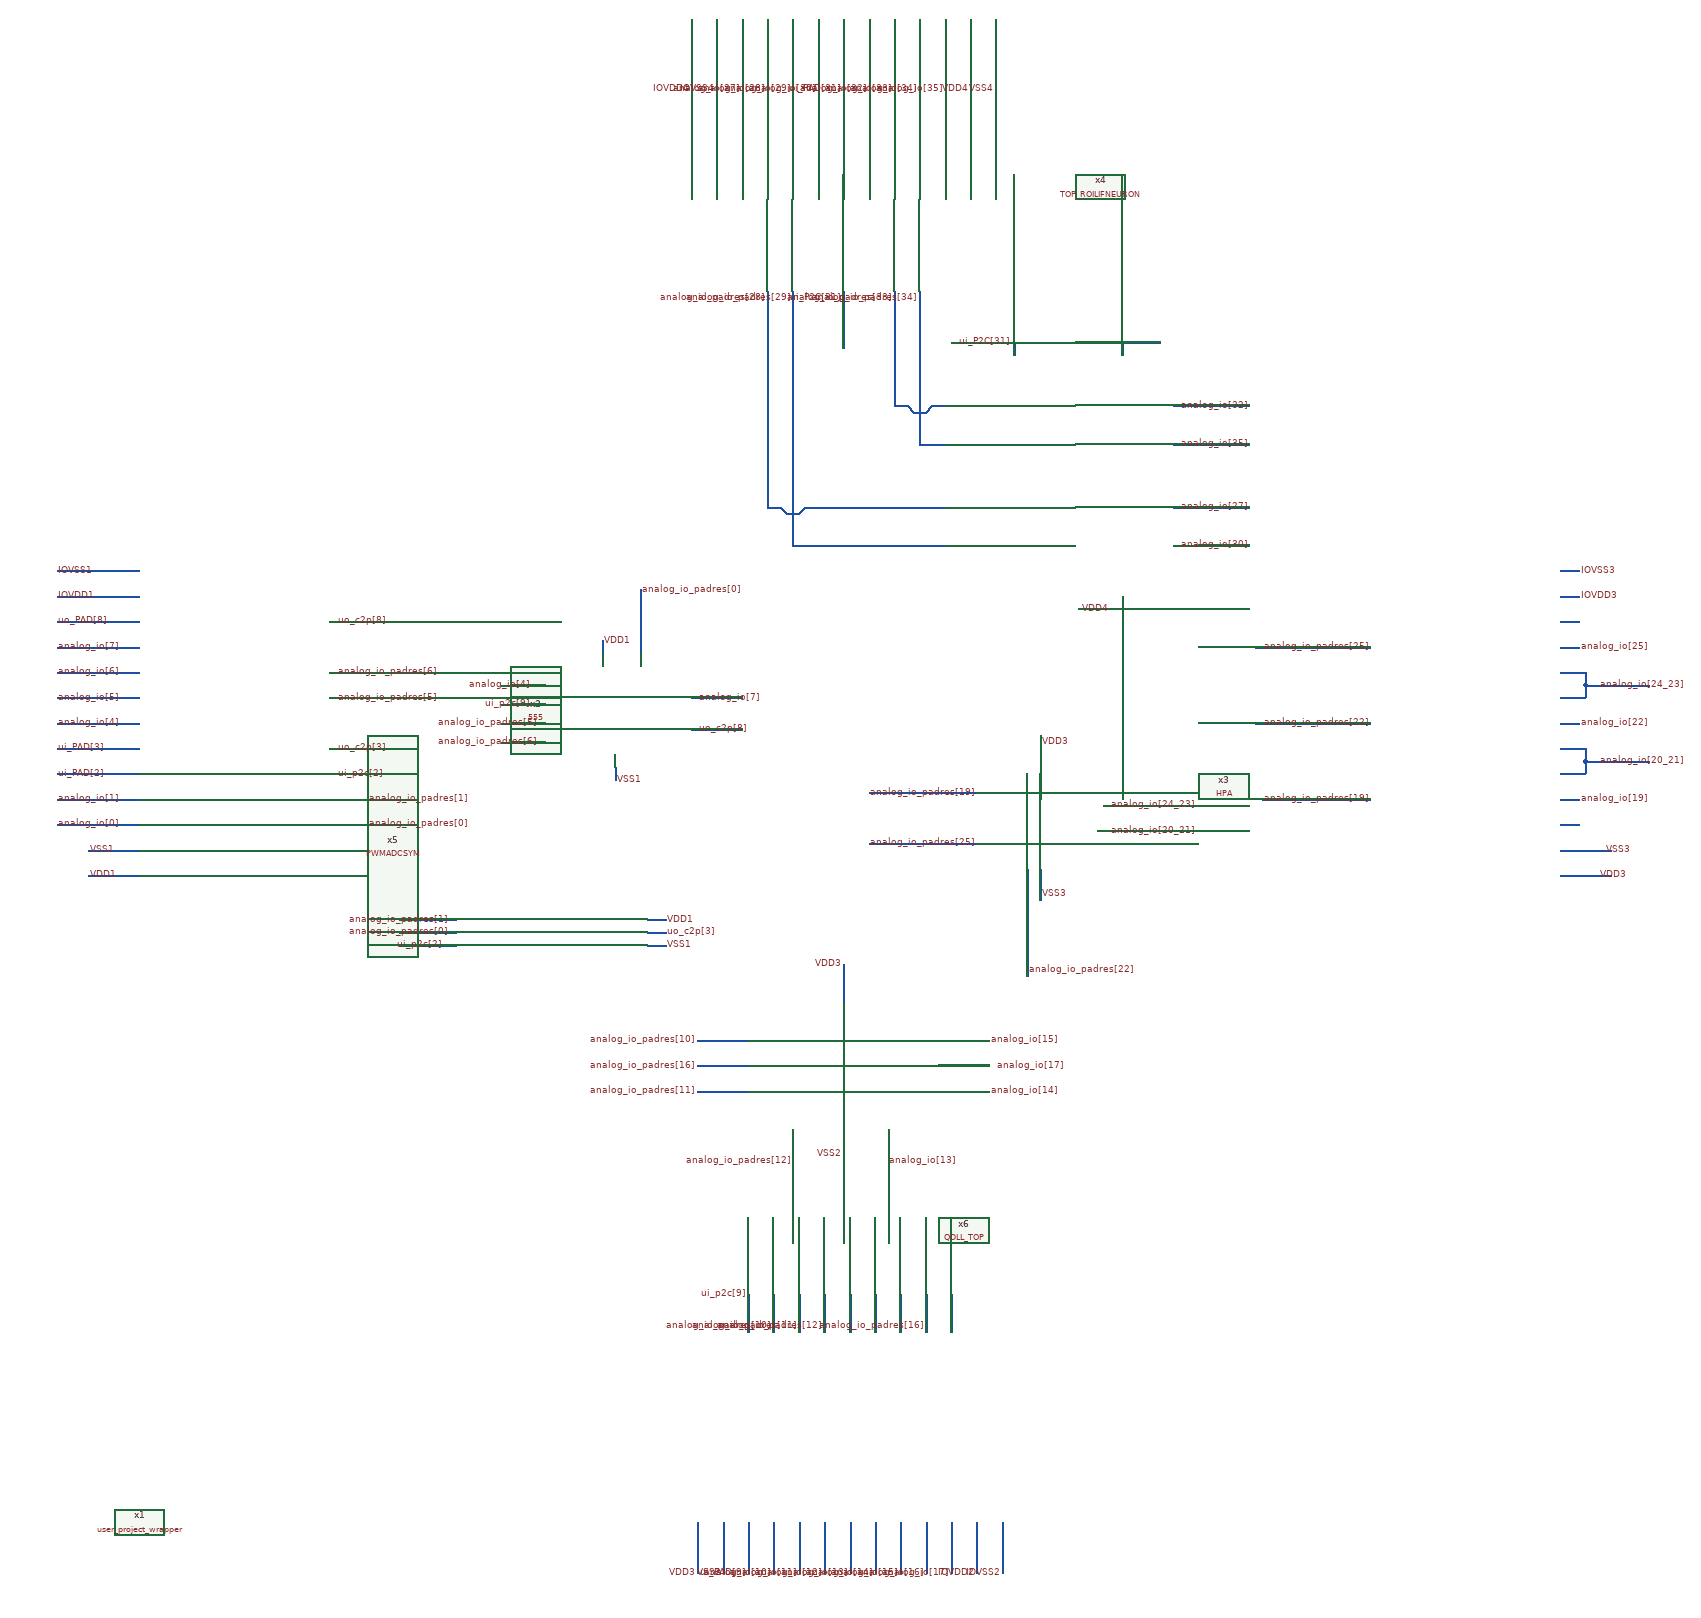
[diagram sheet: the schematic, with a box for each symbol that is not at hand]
v {xschem version=3.4.6 file_version=1.2}
G {}
K {}
V {}
S {}
E {}
N 1550 -1860 1610 -1860 {lab=#net1}
N 1030 -2370 1030 -2240 {lab=analog_io[29]}
N 990 -2370 990 -2240 {lab=analog_io[28]}
N 1230 -2370 1230 -2240 {lab=analog_io[34]}
N 1190 -2370 1190 -2240 {lab=analog_io[33]}
N 1070 -2370 1070 -2240 {lab=analog_io[30]}
N 950 -2370 950 -2240 {lab=analog_io[27]}
N 1110 -2370 1110 -2240 {lab=ui_PAD[31]}
N 1150 -2370 1150 -2240 {lab=analog_io[32]}
N 1270 -2370 1270 -2240 {lab=analog_io[35]}
N 910 -2370 910 -2240 {lab=IOVSS4}
N 870 -2370 870 -2240 {lab=IOVDD4}
N 1350 -2370 1350 -2240 {lab=VSS4}
N 1310 -2370 1310 -2240 {lab=VDD4}
N 1630 -1700 1750 -1700 {lab=analog_io[35]}
N 1630 -1760 1750 -1760 {lab=analog_io[32]}
N 1630 -1600 1750 -1600 {lab=analog_io[27]}
N 1190 -1940 1190 -1760 {lab=analog_io_padres[33]}
N 1630 -1540 1750 -1540 {lab=analog_io[30]}
N 1190 -1760 1210 -1760 {lab=analog_io_padres[33]}
N 1210 -1760 1220 -1750 {lab=analog_io_padres[33]}
N 1220 -1750 1240 -1750 {lab=analog_io_padres[33]}
N 1240 -1750 1250 -1760 {lab=analog_io_padres[33]}
N 990 -1600 1010 -1600 {lab=analog_io_padres[28]}
N 990 -1940 990 -1600 {lab=analog_io_padres[28]}
N 1010 -1600 1020 -1590 {lab=analog_io_padres[28]}
N 1020 -1590 1040 -1590 {lab=analog_io_padres[28]}
N 1040 -1590 1050 -1600 {lab=analog_io_padres[28]}
N 1380 -1860 1380 -1840 {lab=ui_P2C[31]}
N 1280 -1860 1380 -1860 {lab=ui_P2C[31]}
N 1550 -1860 1550 -1840 {lab=#net1}
N 1550 -1460 1550 -1440 {lab=VDD4}
N 1480 -1440 1550 -1440 {lab=VDD4}
N 1250 -1760 1270 -1760 {lab=analog_io_padres[33]}
N 1230 -1700 1270 -1700 {lab=analog_io_padres[34]}
N 1050 -1600 1270 -1600 {lab=analog_io_padres[28]}
N 1030 -1540 1270 -1540 {lab=analog_io_padres[29]}
N 1230 -1940 1230 -1700 {lab=analog_io_padres[34]}
N 1030 -1940 1030 -1540 {lab=analog_io_padres[29]}
N 1110 -1940 1110 -1850 {lab=ui_P2C[31]}
N -130 -1380 0 -1380 {lab=analog_io[7]}
N -130 -1260 0 -1260 {lab=analog_io[4]}
N 570 -1320 640 -1320 {lab=analog_io[4]}
N 870 -1300 950 -1300 {lab=analog_io[7]}
N -80 -1060 0 -1060 {lab=VSS1}
N -80 -1020 0 -1020 {lab=VDD1}
N 800 -950 830 -950 {lab=VDD1}
N 730 -1390 730 -1370 {lab=VDD1}
N 800 -910 830 -910 {lab=VSS1}
N 750 -1190 750 -1170 {lab=VSS1}
N 790 -1470 790 -1370 {lab=analog_io_padres[0]}
N 300 -1100 360 -1100 {lab=analog_io_padres[0]}
N 300 -1140 360 -1140 {lab=analog_io_padres[1]}
N 410 -930 500 -930 {lab=analog_io_padres[0]}
N 410 -950 500 -950 {lab=analog_io_padres[1]}
N 410 -910 500 -910 {lab=ui_p2c[2]}
N 800 -930 830 -930 {lab=uo_c2p[3]}
N 300 -1180 340 -1180 {lab=ui_p2c[2]}
N 300 -1220 340 -1220 {lab=uo_c2p[3]}
N 300 -1340 350 -1340 {lab=analog_io_padres[6]}
N 300 -1300 350 -1300 {lab=analog_io_padres[5]}
N 570 -1290 640 -1290 {lab=ui_p2c[9]}
N 570 -1260 640 -1260 {lab=analog_io_padres[5]}
N 570 -1230 640 -1230 {lab=analog_io_padres[6]}
N 300 -1420 340 -1420 {lab=uo_c2p[8]}
N 870 -1250 950 -1250 {lab=uo_c2p[8]}
N 960 -360 960 -300 {lab=ui_p2c[9]}
N -130 -1100 0 -1100 {lab=analog_io[0]}
N -130 -1140 0 -1140 {lab=analog_io[1]}
N -130 -1180 0 -1180 {lab=ui_PAD[2]}
N -130 -1220 0 -1220 {lab=ui_PAD[3]}
N -130 -1300 0 -1300 {lab=analog_io[5]}
N -130 -1340 0 -1340 {lab=analog_io[6]}
N -130 -1420 0 -1420 {lab=uo_PAD[8]}
N -130 -1500 0 -1500 {lab=IOVSS1}
N -130 -1460 0 -1460 {lab=IOVDD1}
N 1420 -1240 1420 -1190 {lab=VDD3}
N 1420 -1030 1420 -980 {lab=VSS3}
N 2240 -1020 2320 -1020 {lab=VDD3}
N 2240 -1060 2320 -1060 {lab=VSS3}
N 1520 -1130 1620 -1130 {lab=analog_io[24_23]}
N 1510 -1090 1610 -1090 {lab=analog_io[20_21]}
N 2240 -1180 2280 -1180 {lab=analog_io[20_21]}
N 2280 -1200 2280 -1180 {lab=analog_io[20_21]}
N 2240 -1220 2280 -1220 {lab=analog_io[20_21]}
N 2280 -1200 2380 -1200 {lab=analog_io[20_21]}
N 2280 -1220 2280 -1200 {lab=analog_io[20_21]}
N 2240 -1300 2280 -1300 {lab=analog_io[24_23]}
N 2280 -1320 2280 -1300 {lab=analog_io[24_23]}
N 2240 -1340 2280 -1340 {lab=analog_io[24_23]}
N 2280 -1320 2380 -1320 {lab=analog_io[24_23]}
N 2280 -1340 2280 -1320 {lab=analog_io[24_23]}
N 1400 -1030 1400 -860 {lab=analog_io_padres[22]}
N 1760 -1260 1940 -1260 {lab=analog_io_padres[22]}
N 1760 -1380 1940 -1380 {lab=analog_io_padres[25]}
N 1770 -1140 1940 -1140 {lab=analog_io_padres[19]}
N 1150 -1070 1320 -1070 {lab=analog_io_padres[25]}
N 1150 -1150 1320 -1150 {lab=analog_io_padres[19]}
N 2240 -1500 2270 -1500 {lab=IOVSS3}
N 2240 -1460 2270 -1460 {lab=IOVDD3}
N 2240 -1420 2270 -1420 {lab=#net2}
N 2240 -1100 2270 -1100 {lab=#net3}
N 1260 -760 1340 -760 {lab=analog_io[15]}
N 1260 -720 1340 -720 {lab=#net4}
N 1260 -680 1340 -680 {lab=analog_io_padres[14]}
N 880 -760 960 -760 {lab=analog_io_padres[10]}
N 880 -720 960 -720 {lab=analog_io_padres[16]}
N 880 -680 960 -680 {lab=analog_io_padres[11]}
N 1030 -620 1030 -570 {lab=analog_io_padres[12]}
N 1180 -620 1180 -570 {lab=analog_io[13]}
N 2240 -1380 2270 -1380 {lab=analog_io[25]}
N 2240 -1260 2270 -1260 {lab=analog_io[22]}
N 2240 -1140 2270 -1140 {lab=analog_io[19]}
N 880 0 880 80 {lab=VDD3}
N 920 0 920 80 {lab=VSS2}
N 960 0 960 80 {lab=ui_PAD[9]}
N 1000 0 1000 80 {lab=analog_io[10]}
N 1040 0 1040 80 {lab=analog_io[11]}
N 1080 0 1080 80 {lab=analog_io[12]}
N 1120 0 1120 80 {lab=analog_io[13]}
N 1160 0 1160 80 {lab=analog_io[14]}
N 1200 0 1200 80 {lab=analog_io[15]}
N 1240 0 1240 80 {lab=analog_io[16]}
N 1280 0 1280 80 {lab=analog_io[17]}
N 1320 0 1320 80 {lab=IOVDD2}
N 1360 0 1360 80 {lab=IOVSS2}
N 1110 -880 1110 -820 {lab=VDD3}
N 1040 -360 1040 -300 {lab=analog_io_padres[11]}
N 1080 -360 1080 -300 {lab=analog_io_padres[12]}
N 1120 -360 1120 -300 {lab=#net5}
N 1240 -360 1240 -300 {lab=analog_io_padres[16]}
N 1280 -360 1280 -300 {lab=#net6}
N 1000 -360 1000 -300 {lab=analog_io_padres[10]}
N 1110 -620 1110 -570 {lab=VSS2}
N 1200 -360 1200 -300 {lab=#net7}
N 1160 -360 1160 -300 {lab=#net8}
C {user_project_wrapper.sym} 0 0 0 0 {name=x1}
C {IHP__MPC0349/dependencies/IHP__OSC3593/OSC3593-main/schematic/xschem/555.sym} 790 -1300 0 0 {name=x2}
C {IHP__MPC0349/dependencies/IHP__OPA2251/OPA2251-main/schematic/xschem/HPA.sym} 1400 -1110 0 0 {name=x3}
C {IHP__MPC0349/dependencies/IHP__OSC9996/OSC9996-main/schematic/xschem/TOP_ROILIFNEURON.sym} 1250 -1860 2 1 {name=x4}
C {IHP__MPC0349/dependencies/IHP__QDLL6501/QDLL6501-main/schematic/xschem/QDLL_TOP.sym} 1110 -720 0 0 {name=x6}
C {IHP__MPC0349/dependencies/IHP__OSC3593/OSC3593-main/schematic/xschem/PWMADCSYM.sym} 650 -930 0 0 {name=x5}
C {lab_wire.sym} 1640 -1540 2 0 {name=p4 sig_type=std_logic lab=analog_io[30]	}
C {lab_wire.sym} 1640 -1600 2 0 {name=p5 sig_type=std_logic lab=analog_io[27]	}
C {lab_wire.sym} 1640 -1700 2 0 {name=p6 sig_type=std_logic lab=analog_io[35]	}
C {lab_wire.sym} 1640 -1760 2 0 {name=p7 sig_type=std_logic lab=analog_io[32]	}
C {lab_wire.sym} 1530 -1440 0 0 {name=p8 sig_type=std_logic lab=VDD4	}
C {lab_wire.sym} 1420 -990 0 1 {name=p10 sig_type=std_logic lab=VSS3}
C {lab_wire.sym} 1290 -1860 0 1 {name=p11 sig_type=std_logic lab=ui_P2C[31]	}
C {lab_wire.sym} 1030 -2260 1 0 {name=p12 sig_type=std_logic lab=analog_io[29]	}
C {lab_wire.sym} 990 -2260 1 0 {name=p13 sig_type=std_logic lab=analog_io[28]	}
C {lab_wire.sym} 1230 -2260 1 0 {name=p14 sig_type=std_logic lab=analog_io[34]	}
C {lab_wire.sym} 1190 -2260 1 0 {name=p15 sig_type=std_logic lab=analog_io[33]	}
C {lab_wire.sym} 1070 -2260 1 0 {name=p16 sig_type=std_logic lab=analog_io[30]	}
C {lab_wire.sym} 950 -2260 1 0 {name=p17 sig_type=std_logic lab=analog_io[27]	}
C {lab_wire.sym} 1110 -2260 1 0 {name=p18 sig_type=std_logic lab=ui_PAD[31]	}
C {lab_wire.sym} 1150 -2260 1 0 {name=p19 sig_type=std_logic lab=analog_io[32]	}
C {lab_wire.sym} 1270 -2260 1 0 {name=p20 sig_type=std_logic lab=analog_io[35]	}
C {lab_wire.sym} 910 -2260 1 0 {name=p21 sig_type=std_logic lab=IOVSS4	}
C {lab_wire.sym} 870 -2260 1 0 {name=p22 sig_type=std_logic lab=IOVDD4	}
C {lab_wire.sym} 1350 -2260 1 0 {name=p23 sig_type=std_logic lab=VSS4}
C {lab_wire.sym} 1310 -2260 1 0 {name=p24 sig_type=std_logic lab=VDD4	}
C {lab_wire.sym} 990 -1930 3 0 {name=p26 sig_type=std_logic lab=analog_io_padres[28]	}
C {lab_wire.sym} 1030 -1930 3 0 {name=p1 sig_type=std_logic lab=analog_io_padres[29]	}
C {lab_wire.sym} 1230 -1930 1 1 {name=p29 sig_type=std_logic lab=analog_io_padres[34]	}
C {lab_wire.sym} 1190 -1930 1 1 {name=p27 sig_type=std_logic lab=analog_io_padres[33]	}
C {lab_wire.sym} 1110 -1930 3 0 {name=p2 sig_type=std_logic lab=ui_P2C[31]	}
C {lab_wire.sym} 880 -1300 0 1 {name=p3 sig_type=std_logic lab=analog_io[7]	}
C {lab_wire.sym} -130 -1380 2 0 {name=p9 sig_type=std_logic lab=analog_io[7]	}
C {lab_wire.sym} -130 -1260 2 0 {name=p25 sig_type=std_logic lab=analog_io[4]	}
C {lab_wire.sym} 620 -1320 0 0 {name=p28 sig_type=std_logic lab=analog_io[4]	}
C {lab_wire.sym} -80 -1020 2 0 {name=p30 sig_type=std_logic lab=VDD1}
C {lab_wire.sym} -80 -1060 2 0 {name=p31 sig_type=std_logic lab=VSS1}
C {lab_wire.sym} 830 -950 0 1 {name=p32 sig_type=std_logic lab=VDD1}
C {lab_wire.sym} 730 -1390 0 1 {name=p33 sig_type=std_logic lab=VDD1}
C {lab_wire.sym} 750 -1170 2 0 {name=p34 sig_type=std_logic lab=VSS1}
C {lab_wire.sym} 830 -910 0 1 {name=p35 sig_type=std_logic lab=VSS1}
C {lab_wire.sym} 360 -1140 0 1 {name=p36 sig_type=std_logic lab=analog_io_padres[1]	}
C {lab_wire.sym} 360 -1100 0 1 {name=p37 sig_type=std_logic lab=analog_io_padres[0]	}
C {lab_wire.sym} 790 -1470 0 1 {name=p38 sig_type=std_logic lab=analog_io_padres[0]	}
C {lab_wire.sym} 490 -930 0 0 {name=p39 sig_type=std_logic lab=analog_io_padres[0]	}
C {lab_wire.sym} 490 -950 0 0 {name=p40 sig_type=std_logic lab=analog_io_padres[1]	}
C {lab_wire.sym} 310 -1220 0 1 {name=p41 sig_type=std_logic lab=uo_c2p[3]	}
C {lab_wire.sym} 310 -1180 0 1 {name=p42 sig_type=std_logic lab=ui_p2c[2]	}
C {lab_wire.sym} 480 -910 0 0 {name=p43 sig_type=std_logic lab=ui_p2c[2]	}
C {lab_wire.sym} 830 -930 0 1 {name=p44 sig_type=std_logic lab=uo_c2p[3]	}
C {lab_wire.sym} 310 -1340 0 1 {name=p45 sig_type=std_logic lab=analog_io_padres[6]	}
C {lab_wire.sym} 310 -1300 0 1 {name=p46 sig_type=std_logic lab=analog_io_padres[5]	}
C {lab_wire.sym} 630 -1260 0 0 {name=p47 sig_type=std_logic lab=analog_io_padres[5]	}
C {lab_wire.sym} 630 -1230 0 0 {name=p48 sig_type=std_logic lab=analog_io_padres[6]	}
C {lab_wire.sym} 620 -1290 0 0 {name=p49 sig_type=std_logic lab=ui_p2c[9]	}
C {lab_wire.sym} 310 -1420 0 1 {name=p50 sig_type=std_logic lab=uo_c2p[8]	}
C {lab_wire.sym} 880 -1250 0 1 {name=p51 sig_type=std_logic lab=uo_c2p[8]	}
C {lab_wire.sym} 960 -360 0 0 {name=p52 sig_type=std_logic lab=ui_p2c[9]	}
C {lab_wire.sym} -130 -1100 2 0 {name=p53 sig_type=std_logic lab=analog_io[0]	}
C {lab_wire.sym} -130 -1140 2 0 {name=p54 sig_type=std_logic lab=analog_io[1]	}
C {lab_wire.sym} -130 -1180 2 0 {name=p55 sig_type=std_logic lab=ui_PAD[2]	}
C {lab_wire.sym} -130 -1220 2 0 {name=p56 sig_type=std_logic lab=ui_PAD[3]	}
C {lab_wire.sym} -130 -1300 2 0 {name=p57 sig_type=std_logic lab=analog_io[5]	}
C {lab_wire.sym} -130 -1340 2 0 {name=p58 sig_type=std_logic lab=analog_io[6]	}
C {lab_wire.sym} -130 -1420 2 0 {name=p59 sig_type=std_logic lab=uo_PAD[8]	}
C {lab_wire.sym} -130 -1500 2 0 {name=p60 sig_type=std_logic lab=IOVSS1	}
C {lab_wire.sym} -130 -1460 2 0 {name=p61 sig_type=std_logic lab=IOVDD1}
C {lab_wire.sym} 1420 -1230 0 1 {name=p62 sig_type=std_logic lab=VDD3}
C {lab_wire.sym} 2310 -1060 0 1 {name=p63 sig_type=std_logic lab=VSS3}
C {lab_wire.sym} 2300 -1020 0 1 {name=p64 sig_type=std_logic lab=VDD3}
C {lab_wire.sym} 1530 -1090 2 0 {name=p65 sig_type=std_logic lab=analog_io[20_21]	}
C {lab_wire.sym} 1530 -1130 2 0 {name=p66 sig_type=std_logic lab=analog_io[24_23]	}
C {lab_wire.sym} 2300 -1200 2 0 {name=p67 sig_type=std_logic lab=analog_io[20_21]	}
C {lab_wire.sym} 2300 -1320 2 0 {name=p68 sig_type=std_logic lab=analog_io[24_23]	}
C {lab_wire.sym} 1400 -870 0 1 {name=p69 sig_type=std_logic lab=analog_io_padres[22]}
C {lab_wire.sym} 1770 -1260 0 1 {name=p70 sig_type=std_logic lab=analog_io_padres[22]}
C {lab_wire.sym} 1770 -1380 2 0 {name=p71 sig_type=std_logic lab=analog_io_padres[25]	}
C {lab_wire.sym} 1770 -1140 2 0 {name=p72 sig_type=std_logic lab=analog_io_padres[19]}
C {lab_wire.sym} 1150 -1070 2 0 {name=p73 sig_type=std_logic lab=analog_io_padres[25]	}
C {lab_wire.sym} 1150 -1150 2 0 {name=p74 sig_type=std_logic lab=analog_io_padres[19]}
C {noconn.sym} 2270 -1420 2 0 {name=l1}
C {noconn.sym} 2270 -1100 2 0 {name=l4}
C {lab_wire.sym} 2270 -1500 0 1 {name=p75 sig_type=std_logic lab=IOVSS3}
C {lab_wire.sym} 2270 -1460 0 1 {name=p76 sig_type=std_logic lab=IOVDD3}
C {lab_wire.sym} 2270 -1380 2 0 {name=p77 sig_type=std_logic lab=analog_io[25]	}
C {lab_wire.sym} 2270 -1260 2 0 {name=p78 sig_type=std_logic lab=analog_io[22]	}
C {lab_wire.sym} 2270 -1140 2 0 {name=p79 sig_type=std_logic lab=analog_io[19]	}
C {lab_wire.sym} 1360 80 1 1 {name=p80 sig_type=std_logic lab=IOVSS2}
C {lab_wire.sym} 1320 80 1 1 {name=p81 sig_type=std_logic lab=IOVDD2}
C {lab_wire.sym} 920 80 1 1 {name=p82 sig_type=std_logic lab=VSS2}
C {lab_wire.sym} 880 80 1 1 {name=p83 sig_type=std_logic lab=VDD3}
C {lab_wire.sym} 1000 80 3 0 {name=p84 sig_type=std_logic lab=analog_io[10]	}
C {lab_wire.sym} 1040 80 3 0 {name=p85 sig_type=std_logic lab=analog_io[11]	}
C {lab_wire.sym} 1080 80 3 0 {name=p86 sig_type=std_logic lab=analog_io[12]	}
C {lab_wire.sym} 1120 80 3 0 {name=p87 sig_type=std_logic lab=analog_io[13]	}
C {lab_wire.sym} 1160 80 3 0 {name=p88 sig_type=std_logic lab=analog_io[14]	}
C {lab_wire.sym} 1200 80 3 0 {name=p89 sig_type=std_logic lab=analog_io[15]	}
C {lab_wire.sym} 1240 80 3 0 {name=p90 sig_type=std_logic lab=analog_io[16]	}
C {lab_wire.sym} 1280 80 3 0 {name=p91 sig_type=std_logic lab=analog_io[17]	}
C {lab_pin.sym} 1000 -310 1 0 {name=p111 sig_type=std_logic lab=analog_io_padres[10]}
C {lab_pin.sym} 1040 -310 1 0 {name=p112 sig_type=std_logic lab=analog_io_padres[11]}
C {lab_pin.sym} 1080 -310 1 0 {name=p113 sig_type=std_logic lab=analog_io_padres[12]}
C {lab_pin.sym} 1340 -680 2 0 {name=p115 sig_type=std_logic lab=analog_io[14]}
C {lab_pin.sym} 1240 -310 1 0 {name=p117 sig_type=std_logic lab=analog_io_padres[16]}
C {lab_pin.sym} 880 -760 0 0 {name=p92 sig_type=std_logic lab=analog_io_padres[10]}
C {lab_pin.sym} 880 -680 0 0 {name=p93 sig_type=std_logic lab=analog_io_padres[11]}
C {lab_pin.sym} 1030 -570 0 0 {name=p94 sig_type=std_logic lab=analog_io_padres[12]}
C {lab_pin.sym} 1180 -570 2 0 {name=p95 sig_type=std_logic lab=analog_io[13]}
C {lab_wire.sym} 1110 -580 2 1 {name=p96 sig_type=std_logic lab=VSS2}
C {lab_wire.sym} 1110 -880 2 1 {name=p97 sig_type=std_logic lab=VDD3}
C {lab_pin.sym} 1340 -760 2 0 {name=p99 sig_type=std_logic lab=analog_io[15]}
C {lab_pin.sym} 880 -720 0 0 {name=p100 sig_type=std_logic lab=analog_io_padres[16]}
C {lab_pin.sym} 1350 -720 2 0 {name=p101 sig_type=std_logic lab=analog_io[17]}
C {lab_wire.sym} 960 80 3 0 {name=p102 sig_type=std_logic lab=ui_PAD[9]	}
C {noconn.sym} 1160 -360 1 0 {name=l2}
C {noconn.sym} 1200 -360 1 0 {name=l3}
C {noconn.sym} 1280 -360 1 0 {name=l5}
C {noconn.sym} 1120 -360 1 0 {name=l6}
